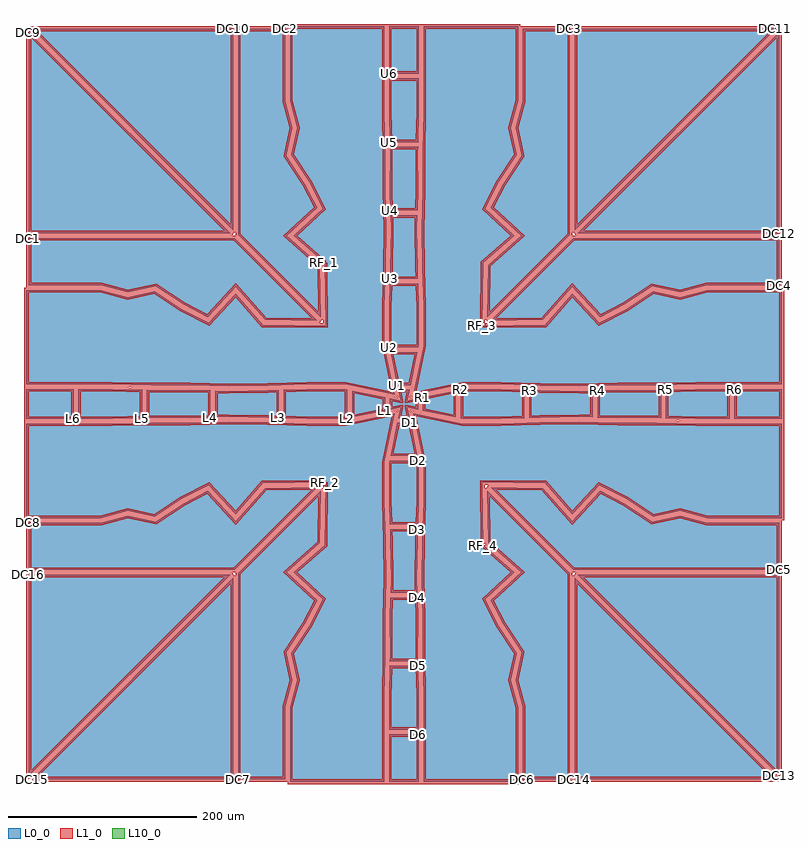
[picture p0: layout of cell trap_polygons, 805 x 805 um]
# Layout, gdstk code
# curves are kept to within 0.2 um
import gdstk
lib = gdstk.Library(unit=1e-6, precision=1e-09)
def P(c, l, *ps):  # polygons
    for p in ps: c.add(gdstk.Polygon(p, *l))
L0_0 = (0, 0)
L1_0 = (1, 0)
L10_0 = (10, 0)

trap_polygons = lib.new_cell('trap_polygons')
P(trap_polygons, L0_0, [(-397.5,-180.75),(-184.286,-180.75),(-397.5,-393.964),(-397.5,-180.75)],
  [(-393.964,-397.5),(-180.75,-184.286),(-180.75,-397.5),(-393.964,-397.5)],
  [(180.75,-397.5),(180.75,-184.286),(393.964,-397.5),(180.75,-397.5)],
  [(397.5,-393.964),(184.286,-180.75),(397.5,-180.75),(397.5,-393.964)],
  [(397.5,180.75),(184.286,180.75),(397.5,393.964),(397.5,180.75)],
  [(393.964,397.5),(180.75,184.286),(180.75,397.5),(393.964,397.5)],
  [(-180.75,397.5),(-180.75,184.286),(-393.964,397.5),(-180.75,397.5)],
  [(-397.5,393.964),(-184.286,180.75),(-397.5,180.75),(-397.5,393.964)],
  [(-397.5,-125.75),(-320.7,-125.75),(-292.572,-118.384),(-263.035,-124.717),(-232.858,-104.912),(-207.802,-92.104),(-177.951,-124.103),(-147.115,-89.006),(-91.738,-88.202),(-179.286,-175.75),(-397.5,-175.75)],
  [(-175.75,-397.5),(-175.75,-179.286),(-88.202,-91.738),(-89.006,-147.115),(-124.103,-177.951),(-92.104,-207.802),(-104.912,-232.858),(-124.717,-263.035),(-118.384,-292.572),(-125.75,-320.7),(-125.75,-397.5)],
  [(125.75,-397.5),(125.75,-320.7),(118.384,-292.572),(124.717,-263.035),(104.912,-232.858),(92.104,-207.802),(124.103,-177.951),(89.006,-147.115),(88.202,-91.738),(175.75,-179.286),(175.75,-397.5)],
  [(397.5,-175.75),(179.286,-175.75),(91.738,-88.202),(147.115,-89.006),(177.951,-124.103),(207.802,-92.104),(232.858,-104.912),(263.035,-124.717),(292.572,-118.384),(320.7,-125.75),(397.5,-125.75)],
  [(397.5,125.75),(320.7,125.75),(292.572,118.384),(263.035,124.717),(232.858,104.912),(207.802,92.104),(177.951,124.103),(147.115,89.006),(91.738,88.202),(179.286,175.75),(397.5,175.75)],
  [(175.75,397.5),(175.75,179.286),(88.202,91.738),(89.006,147.115),(124.103,177.951),(92.104,207.802),(104.912,232.858),(124.717,263.035),(118.384,292.572),(125.75,320.7),(125.75,397.5)],
  [(-125.75,397.5),(-125.75,320.7),(-118.384,292.572),(-124.717,263.035),(-104.912,232.858),(-92.104,207.802),(-124.103,177.951),(-89.006,147.115),(-88.202,91.738),(-175.75,179.286),(-175.75,397.5)],
  [(-397.5,175.75),(-179.286,175.75),(-91.738,88.202),(-147.115,89.006),(-177.951,124.103),(-207.802,92.104),(-232.858,104.912),(-263.035,124.717),(-292.572,118.384),(-320.7,125.75),(-397.5,125.75)],
  [(-15.75,350),(-15.75,400),(15.75,400),(15.75,350),(-15.75,350)],
  [(350,15.75),(400,15.75),(400,-15.75),(350,-15.75),(350,15.75)],
  [(15.75,-350),(15.75,-400),(-15.75,-400),(-15.75,-350),(15.75,-350)],
  [(-350,-15.75),(-400,-15.75),(-400,15.75),(-350,15.75),(-350,-15.75)],
  [(-15,277.5),(-15.743,309.205),(-15.75,345),(15.75,345),(15.743,309.205),(15,277.5),(-15,277.5)],
  [(277.5,15),(309.205,15.743),(345,15.75),(345,-15.75),(309.205,-15.743),(277.5,-15),(277.5,15)],
  [(15,-277.5),(15.743,-309.205),(15.75,-345),(-15.75,-345),(-15.743,-309.205),(-15,-277.5),(15,-277.5)],
  [(-277.5,-15),(-309.205,-15.743),(-345,-15.75),(-345,15.75),(-309.205,15.743),(-277.5,15),(-277.5,-15)],
  [(-14.333,205),(-14.97,226.593),(-14.772,267.734),(-14.883,272.5),(14.883,272.5),(14.772,267.734),(14.97,226.593),(14.333,205),(-14.333,205)],
  [(205,14.333),(226.593,14.97),(267.734,14.772),(272.5,14.883),(272.5,-14.883),(267.734,-14.772),(226.593,-14.97),(205,-14.333),(205,14.333)],
  [(14.333,-205),(14.97,-226.593),(14.772,-267.734),(14.883,-272.5),(-14.883,-272.5),(-14.772,-267.734),(-14.97,-226.593),(-14.333,-205),(14.333,-205)],
  [(-205,-14.333),(-226.593,-14.97),(-267.734,-14.772),(-272.5,-14.883),(-272.5,14.883),(-267.734,14.772),(-226.593,14.97),(-205,14.333),(-205,-14.333)],
  [(-14.77,132.5),(-14.386,144.098),(-13.755,185.411),(-14.185,200),(14.185,200),(13.755,185.411),(14.386,144.098),(14.77,132.5),(-14.77,132.5)],
  [(132.5,14.77),(144.098,14.386),(185.411,13.755),(200,14.185),(200,-14.185),(185.411,-13.755),(144.098,-14.386),(132.5,-14.77),(132.5,14.77)],
  [(14.77,-132.5),(14.386,-144.098),(13.755,-185.411),(14.185,-200),(-14.185,-200),(-13.755,-185.411),(-14.386,-144.098),(-14.77,-132.5),(14.77,-132.5)],
  [(-132.5,-14.77),(-144.098,-14.386),(-185.411,-13.755),(-200,-14.185),(-200,14.185),(-185.411,13.755),(-144.098,14.386),(-132.5,14.77),(-132.5,-14.77)],
  [(-15.25,60),(-15.75,62.418),(-15.75,102.98),(-14.936,127.5),(14.936,127.5),(15.75,102.98),(15.75,62.418),(15.25,60),(-15.25,60)],
  [(60,15.25),(62.418,15.75),(102.98,15.75),(127.5,14.936),(127.5,-14.936),(102.98,-15.75),(62.418,-15.75),(60,-15.25),(60,15.25)],
  [(15.25,-60),(15.75,-62.418),(15.75,-102.98),(14.936,-127.5),(-14.936,-127.5),(-15.75,-102.98),(-15.75,-62.418),(-15.25,-60),(15.25,-60)],
  [(-60,-15.25),(-62.418,-15.75),(-102.98,-15.75),(-127.5,-14.936),(-127.5,14.936),(-102.98,15.75),(-62.418,15.75),(-60,15.25),(-60,-15.25)],
  [(-6.978,20),(-14.216,55),(14.216,55),(6.978,20),(-6.978,20)],
  [(20,6.978),(55,14.216),(55,-14.216),(20,-6.978),(20,6.978)],
  [(6.978,-20),(14.216,-55),(-14.216,-55),(-6.978,-20),(6.978,-20)],
  [(-20,-6.978),(-55,-14.216),(-55,14.216),(-20,6.978),(-20,-6.978)],
  [(-5.944,15),(5.944,15),(3.584,3.584),(15,5.944),(15,-5.944),(3.584,-3.584),(5.944,-15),(-5.944,-15),(-3.584,-3.584),(-15,-5.944),(-15,5.944),(-3.584,3.584)],
  [(84.038,-149.406),(116.654,-178.062),(85.935,-206.719),(100.583,-235.375),(119.39,-264.031),(113.246,-292.687),(120.75,-321.344),(120.75,-400),(20.75,-400),(20.736,-308.844),(19.772,-267.687),(19.97,-226.531),(18.756,-185.375),(19.384,-144.219),(20.75,-103.062),(20.75,-61.906),(10.02,-10.02),(61.906,-20.75),(103.062,-20.75),(144.219,-19.384),(185.375,-18.756),(226.531,-19.97),(267.687,-19.772),(308.844,-20.736),(400,-20.75),(400,-120.75),(321.344,-120.75),(292.687,-113.246),(264.031,-119.39),(235.375,-100.583),(206.719,-85.935),(178.062,-116.654),(149.406,-84.038),(83.076,-83.076)],
  [(83.076,83.076),(149.406,84.038),(178.062,116.654),(206.719,85.935),(235.375,100.583),(264.031,119.39),(292.687,113.246),(321.344,120.75),(400,120.75),(400,20.75),(308.844,20.736),(267.687,19.772),(226.531,19.97),(185.375,18.756),(144.219,19.384),(103.062,20.75),(61.906,20.75),(10.02,10.02),(20.75,61.906),(20.75,103.062),(19.384,144.219),(18.756,185.375),(19.97,226.531),(19.772,267.687),(20.736,308.844),(20.75,400),(120.75,400),(120.75,321.344),(113.246,292.687),(119.39,264.031),(100.583,235.375),(85.935,206.719),(116.654,178.062),(84.038,149.406)],
  [(-83.076,-83.076),(-149.406,-84.038),(-178.062,-116.654),(-206.719,-85.935),(-235.375,-100.583),(-264.031,-119.39),(-292.687,-113.246),(-321.344,-120.75),(-400,-120.75),(-400,-20.75),(-308.844,-20.736),(-267.687,-19.772),(-226.531,-19.97),(-185.375,-18.756),(-144.219,-19.384),(-103.062,-20.75),(-61.906,-20.75),(-10.02,-10.02),(-20.75,-61.906),(-20.75,-103.062),(-19.384,-144.219),(-18.756,-185.375),(-19.97,-226.531),(-19.772,-267.687),(-20.736,-308.844),(-20.75,-400),(-120.75,-400),(-120.75,-321.344),(-113.246,-292.687),(-119.39,-264.031),(-100.583,-235.375),(-85.935,-206.719),(-116.654,-178.062),(-84.038,-149.406)],
  [(-84.038,149.406),(-116.654,178.062),(-85.935,206.719),(-100.583,235.375),(-119.39,264.031),(-113.246,292.687),(-120.75,321.344),(-120.75,400),(-20.75,400),(-20.736,308.844),(-19.772,267.687),(-19.97,226.531),(-18.756,185.375),(-19.384,144.219),(-20.75,103.062),(-20.75,61.906),(-10.02,10.02),(-61.906,20.75),(-103.062,20.75),(-144.219,19.384),(-185.375,18.756),(-226.531,19.97),(-267.687,19.772),(-308.844,20.736),(-400,20.75),(-400,120.75),(-321.344,120.75),(-292.687,113.246),(-264.031,119.39),(-235.375,100.583),(-206.719,85.935),(-178.062,116.654),(-149.406,84.038),(-83.076,83.076)])
P(trap_polygons, L1_0, [(-397.5,-178.25),(-397.5,-183.25),(-190.321,-183.25),(-395,-387.929),(-395,-180.75),(-400,-180.75),(-400,-396.464),(-397.5,-397.5),(-180.75,-180.75),(-181.786,-178.25)],
  [(-395.732,-395.732),(-392.197,-399.268),(-183.25,-190.321),(-183.25,-395),(-393.964,-395),(-393.964,-400),(-178.25,-400),(-178.25,-181.786),(-180.75,-180.75)],
  [(178.25,-397.5),(183.25,-397.5),(183.25,-190.321),(387.929,-395),(180.75,-395),(180.75,-400),(396.464,-400),(397.5,-397.5),(180.75,-180.75),(178.25,-181.786)],
  [(395.732,-395.732),(399.268,-392.197),(190.321,-183.25),(395,-183.25),(395,-393.964),(400,-393.964),(400,-178.25),(181.786,-178.25),(180.75,-180.75)],
  [(397.5,178.25),(397.5,183.25),(190.321,183.25),(395,387.929),(395,180.75),(400,180.75),(400,396.464),(397.5,397.5),(180.75,180.75),(181.786,178.25)],
  [(395.732,395.732),(392.197,399.268),(183.25,190.321),(183.25,395),(393.964,395),(393.964,400),(178.25,400),(178.25,181.786),(180.75,180.75)],
  [(-178.25,397.5),(-183.25,397.5),(-183.25,190.321),(-387.929,395),(-180.75,395),(-180.75,400),(-396.464,400),(-397.5,397.5),(-180.75,180.75),(-178.25,181.786)],
  [(-395.732,395.732),(-399.268,392.197),(-190.321,183.25),(-395,183.25),(-395,393.964),(-400,393.964),(-400,178.25),(-181.786,178.25),(-180.75,180.75)],
  [(-397.5,-123.25),(-397.5,-128.25),(-320.378,-128.25),(-292.514,-120.954),(-262.538,-127.38),(-231.6,-107.077),(-208.343,-95.189),(-178.074,-127.637),(-177.723,-127.632),(-145.969,-91.489),(-97.862,-90.791),(-180.321,-173.25),(-395,-173.25),(-395,-125.75),(-400,-125.75),(-400,-178.25),(-178.25,-178.25),(-88.202,-88.202),(-89.274,-85.666),(-148.261,-86.522),(-178.007,-120.379),(-207.26,-89.02),(-234.117,-102.748),(-263.533,-122.053),(-292.63,-115.815),(-321.022,-123.25)],
  [(-178.25,-397.5),(-173.25,-397.5),(-173.25,-180.321),(-90.791,-97.862),(-91.489,-145.969),(-127.632,-177.723),(-127.637,-178.074),(-95.189,-208.343),(-107.077,-231.6),(-127.38,-262.538),(-120.954,-292.514),(-128.25,-320.378),(-128.25,-395),(-175.75,-395),(-175.75,-400),(-123.25,-400),(-123.25,-321.022),(-115.815,-292.63),(-122.053,-263.533),(-102.748,-234.117),(-89.02,-207.26),(-120.379,-178.007),(-86.522,-148.261),(-85.666,-89.274),(-88.202,-88.202),(-178.25,-178.25)],
  [(123.25,-397.5),(128.25,-397.5),(128.25,-320.378),(120.954,-292.514),(127.38,-262.538),(107.077,-231.6),(95.189,-208.343),(127.637,-178.074),(127.632,-177.723),(91.489,-145.969),(90.791,-97.862),(173.25,-180.321),(173.25,-395),(125.75,-395),(125.75,-400),(178.25,-400),(178.25,-178.25),(88.202,-88.202),(85.666,-89.274),(86.522,-148.261),(120.379,-178.007),(89.02,-207.26),(102.748,-234.117),(122.053,-263.533),(115.815,-292.63),(123.25,-321.022)],
  [(397.5,-178.25),(397.5,-173.25),(180.321,-173.25),(97.862,-90.791),(145.969,-91.489),(177.723,-127.632),(178.074,-127.637),(208.343,-95.189),(231.6,-107.077),(262.538,-127.38),(292.514,-120.954),(320.378,-128.25),(395,-128.25),(395,-175.75),(400,-175.75),(400,-123.25),(321.022,-123.25),(292.63,-115.815),(263.533,-122.053),(234.117,-102.748),(207.26,-89.02),(178.007,-120.379),(148.261,-86.522),(89.274,-85.666),(88.202,-88.202),(178.25,-178.25)],
  [(397.5,123.25),(397.5,128.25),(320.378,128.25),(292.514,120.954),(262.538,127.38),(231.6,107.077),(208.343,95.189),(178.074,127.637),(177.723,127.632),(145.969,91.489),(97.862,90.791),(180.321,173.25),(395,173.25),(395,125.75),(400,125.75),(400,178.25),(178.25,178.25),(88.202,88.202),(89.274,85.666),(148.261,86.522),(178.007,120.379),(207.26,89.02),(234.117,102.748),(263.533,122.053),(292.63,115.815),(321.022,123.25)],
  [(178.25,397.5),(173.25,397.5),(173.25,180.321),(90.791,97.862),(91.489,145.969),(127.632,177.723),(127.637,178.074),(95.189,208.343),(107.077,231.6),(127.38,262.538),(120.954,292.514),(128.25,320.378),(128.25,395),(175.75,395),(175.75,400),(123.25,400),(123.25,321.022),(115.815,292.63),(122.053,263.533),(102.748,234.117),(89.02,207.26),(120.379,178.007),(86.522,148.261),(85.666,89.274),(88.202,88.202),(178.25,178.25)],
  [(-123.25,397.5),(-128.25,397.5),(-128.25,320.378),(-120.954,292.514),(-127.38,262.538),(-107.077,231.6),(-95.189,208.343),(-127.637,178.074),(-127.632,177.723),(-91.489,145.969),(-90.791,97.862),(-173.25,180.321),(-173.25,395),(-125.75,395),(-125.75,400),(-178.25,400),(-178.25,178.25),(-88.202,88.202),(-85.666,89.274),(-86.522,148.261),(-120.379,178.007),(-89.02,207.26),(-102.748,234.117),(-122.053,263.533),(-115.815,292.63),(-123.25,321.022)],
  [(-397.5,178.25),(-397.5,173.25),(-180.321,173.25),(-97.862,90.791),(-145.969,91.489),(-177.723,127.632),(-178.074,127.637),(-208.343,95.189),(-231.6,107.077),(-262.538,127.38),(-292.514,120.954),(-320.378,128.25),(-395,128.25),(-395,175.75),(-400,175.75),(-400,123.25),(-321.022,123.25),(-292.63,115.815),(-263.533,122.053),(-234.117,102.748),(-207.26,89.02),(-178.007,120.379),(-148.261,86.522),(-89.274,85.666),(-88.202,88.202),(-178.25,178.25)],
  [(-18.25,350),(-13.25,350),(-13.25,397.5),(13.25,397.5),(13.25,352.5),(-15.75,352.5),(-15.75,347.5),(18.25,347.5),(18.25,402.5),(-18.25,402.5)],
  [(350,18.25),(350,13.25),(397.5,13.25),(397.5,-13.25),(352.5,-13.25),(352.5,15.75),(347.5,15.75),(347.5,-18.25),(402.5,-18.25),(402.5,18.25)],
  [(18.25,-350),(13.25,-350),(13.25,-397.5),(-13.25,-397.5),(-13.25,-352.5),(15.75,-352.5),(15.75,-347.5),(-18.25,-347.5),(-18.25,-402.5),(18.25,-402.5)],
  [(-350,-18.25),(-350,-13.25),(-397.5,-13.25),(-397.5,13.25),(-352.5,13.25),(-352.5,-15.75),(-347.5,-15.75),(-347.5,18.25),(-402.5,18.25),(-402.5,-18.25)],
  [(-17.5,277.441),(-12.501,277.559),(-13.243,309.235),(-13.249,342.5),(13.249,342.5),(13.243,309.235),(12.558,280),(-15,280),(-15,275),(17.443,275),(18.243,309.176),(18.25,347.5),(-18.251,347.499),(-18.243,309.176)],
  [(277.441,17.5),(277.559,12.501),(309.235,13.243),(342.5,13.249),(342.5,-13.249),(309.235,-13.243),(280,-12.558),(280,15),(275,15),(275,-17.443),(309.176,-18.243),(347.5,-18.25),(347.499,18.251),(309.176,18.243)],
  [(17.5,-277.441),(12.501,-277.559),(13.243,-309.235),(13.249,-342.5),(-13.249,-342.5),(-13.243,-309.235),(-12.558,-280),(15,-280),(15,-275),(-17.443,-275),(-18.243,-309.176),(-18.25,-347.5),(18.251,-347.499),(18.243,-309.176)],
  [(-277.441,-17.5),(-277.559,-12.501),(-309.235,-13.243),(-342.5,-13.249),(-342.5,13.249),(-309.235,13.243),(-280,12.558),(-280,-15),(-275,-15),(-275,17.443),(-309.176,18.243),(-347.5,18.25),(-347.499,-18.251),(-309.176,-18.243)],
  [(-16.832,204.926),(-11.834,205.074),(-12.47,226.624),(-12.324,270),(12.324,270),(12.47,226.624),(11.906,207.5),(-14.333,207.5),(-14.333,202.5),(16.76,202.5),(17.47,226.562),(17.383,275),(-17.441,274.941),(-17.47,226.562)],
  [(204.926,16.832),(205.074,11.834),(226.624,12.47),(270,12.324),(270,-12.324),(226.624,-12.47),(207.5,-11.906),(207.5,14.333),(202.5,14.333),(202.5,-16.76),(226.562,-17.47),(275,-17.383),(274.941,17.441),(226.562,17.47)],
  [(16.832,-204.926),(11.834,-205.074),(12.47,-226.624),(12.324,-270),(-12.324,-270),(-12.47,-226.624),(-11.906,-207.5),(14.333,-207.5),(14.333,-202.5),(-16.76,-202.5),(-17.47,-226.562),(-17.383,-275),(17.441,-274.941),(17.47,-226.562)],
  [(-204.926,-16.832),(-205.074,-11.834),(-226.624,-12.47),(-270,-12.324),(-270,12.324),(-226.624,12.47),(-207.5,11.906),(-207.5,-14.333),(-202.5,-14.333),(-202.5,16.76),(-226.562,17.47),(-275,17.383),(-274.941,-17.441),(-226.562,-17.47)],
  [(-17.269,132.583),(-12.272,132.417),(-11.254,185.428),(-11.611,197.5),(11.611,197.5),(11.254,185.428),(12.186,135),(-14.77,135),(-14.77,130),(17.352,130.084),(16.256,185.393),(16.685,202.5),(-16.758,202.425),(-16.256,185.393)],
  [(132.583,17.269),(132.417,12.272),(185.428,11.254),(197.5,11.611),(197.5,-11.611),(185.428,-11.254),(135,-12.186),(135,14.77),(130,14.77),(130.084,-17.352),(185.393,-16.256),(202.5,-16.685),(202.425,16.758),(185.393,16.256)],
  [(17.269,-132.583),(12.272,-132.417),(11.254,-185.428),(11.611,-197.5),(-11.611,-197.5),(-11.254,-185.428),(-12.186,-135),(14.77,-135),(14.77,-130),(-17.352,-130.084),(-16.256,-185.393),(-16.685,-202.5),(16.758,-202.425),(16.256,-185.393)],
  [(-132.583,-17.269),(-132.417,-12.272),(-185.428,-11.254),(-197.5,-11.611),(-197.5,11.611),(-185.428,11.254),(-135,12.186),(-135,-14.77),(-130,-14.77),(-130.084,17.352),(-185.393,16.256),(-202.5,16.685),(-202.425,-16.758),(-185.393,-16.256)],
  [(-17.698,59.494),(-12.802,60.506),(-13.25,62.674),(-13.25,102.938),(-12.518,125),(12.518,125),(13.25,102.938),(13.214,62.5),(-15.25,62.5),(-15.25,57.5),(17.286,57.5),(18.25,62.162),(18.25,103.021),(17.355,130),(-17.355,130),(-18.25,103.021),(-18.25,62.162)],
  [(59.494,17.698),(60.506,12.802),(62.674,13.25),(102.938,13.25),(125,12.518),(125,-12.518),(102.938,-13.25),(62.5,-13.214),(62.5,15.25),(57.5,15.25),(57.5,-17.286),(62.162,-18.25),(103.021,-18.25),(130,-17.355),(130,17.355),(103.021,18.25),(62.162,18.25)],
  [(17.698,-59.494),(12.802,-60.506),(13.25,-62.674),(13.25,-102.938),(12.518,-125),(-12.518,-125),(-13.25,-102.938),(-13.214,-62.5),(15.25,-62.5),(15.25,-57.5),(-17.286,-57.5),(-18.25,-62.162),(-18.25,-103.021),(-17.355,-130),(17.355,-130),(18.25,-103.021),(18.25,-62.162)],
  [(-59.494,-17.698),(-60.506,-12.802),(-62.674,-13.25),(-102.938,-13.25),(-125,-12.518),(-125,12.518),(-102.938,13.25),(-62.5,13.214),(-62.5,-15.25),(-57.5,-15.25),(-57.5,17.286),(-62.162,18.25),(-103.021,18.25),(-130,17.355),(-130,-17.355),(-103.021,-18.25),(-62.162,-18.25)],
  [(-9.427,19.494),(-4.53,20.506),(-11.146,52.5),(11.146,52.5),(4.942,22.5),(-6.978,22.5),(-6.978,17.5),(9.014,17.5),(17.171,56.942),(16.716,57.5),(-16.716,57.5),(-17.171,56.942)],
  [(19.494,9.427),(20.506,4.53),(52.5,11.146),(52.5,-11.146),(22.5,-4.942),(22.5,6.978),(17.5,6.978),(17.5,-9.014),(56.942,-17.171),(57.5,-16.716),(57.5,16.716),(56.942,17.171)],
  [(9.427,-19.494),(4.53,-20.506),(11.146,-52.5),(-11.146,-52.5),(-4.942,-22.5),(6.978,-22.5),(6.978,-17.5),(-9.014,-17.5),(-17.171,-56.942),(-16.716,-57.5),(16.716,-57.5),(17.171,-56.942)],
  [(-19.494,-9.427),(-20.506,-4.53),(-52.5,-11.146),(-52.5,11.146),(-22.5,4.942),(-22.5,-6.978),(-17.5,-6.978),(-17.5,9.014),(-56.942,17.171),(-57.5,16.716),(-57.5,-16.716),(-56.942,-17.171)],
  [(-5.944,17.5),(-5.944,12.5),(2.875,12.5),(0.629,1.642),(1.642,0.629),(12.5,2.875),(12.5,-2.875),(1.642,-0.629),(0.629,-1.642),(2.875,-12.5),(-2.875,-12.5),(-0.629,-1.642),(-1.642,-0.629),(-12.5,-2.875),(-12.5,2.875),(-1.642,0.629),(-0.629,1.642),(-3.496,15.506),(-8.393,14.494),(-6.802,6.802),(-16.942,8.899),(-17.5,8.444),(-17.5,-8.444),(-16.942,-8.899),(-6.802,-6.802),(-8.899,-16.942),(-8.444,-17.5),(8.444,-17.5),(8.899,-16.942),(6.802,-6.802),(16.942,-8.899),(17.5,-8.444),(17.5,8.444),(16.942,8.899),(6.802,6.802),(8.899,16.942),(8.444,17.5)],
  [(85.688,-147.528),(82.388,-151.284),(112.93,-178.118),(82.851,-206.177),(98.419,-236.633),(116.726,-264.529),(110.677,-292.745),(118.25,-321.666),(118.25,-397.5),(23.25,-397.5),(23.235,-308.814),(22.272,-267.664),(22.47,-226.5),(21.257,-185.357),(21.884,-144.279),(23.25,-103.104),(23.25,-61.65),(13.239,-13.239),(61.65,-23.25),(103.104,-23.25),(144.279,-21.884),(185.357,-21.257),(226.5,-22.47),(267.664,-22.272),(308.814,-23.235),(397.5,-23.25),(397.5,-118.25),(321.666,-118.25),(292.745,-110.677),(264.529,-116.726),(236.633,-98.419),(206.177,-82.851),(178.118,-112.93),(150.552,-81.555),(80.613,-80.54),(81.538,-149.443),(86.538,-149.37),(85.613,-85.613),(148.261,-86.522),(177.834,-120.183),(178.185,-120.188),(207.26,-89.02),(234.117,-102.748),(263.533,-122.053),(292.63,-115.815),(321.022,-123.25),(402.5,-123.25),(402.5,-18.25),(308.873,-18.236),(267.711,-17.272),(226.562,-17.47),(185.393,-16.256),(144.158,-16.885),(103.021,-18.25),(62.162,-18.25),(8.079,-7.066),(7.066,-8.079),(18.25,-62.162),(18.25,-103.021),(16.885,-144.158),(16.256,-185.393),(17.47,-226.562),(17.272,-267.711),(18.236,-308.873),(18.25,-402.5),(123.25,-402.5),(123.25,-321.022),(115.815,-292.63),(122.053,-263.533),(102.748,-234.117),(89.02,-207.26),(120.188,-178.185),(120.183,-177.834)],
  [(83.04,85.576),(83.112,80.576),(150.552,81.555),(178.118,112.93),(206.177,82.851),(236.633,98.419),(264.529,116.726),(292.745,110.677),(321.666,118.25),(397.5,118.25),(397.5,23.25),(308.814,23.235),(267.664,22.272),(226.5,22.47),(185.357,21.257),(144.279,21.884),(103.104,23.25),(61.65,23.25),(13.239,13.239),(23.25,61.65),(23.25,103.104),(21.884,144.279),(21.257,185.357),(22.47,226.5),(22.272,267.664),(23.235,308.814),(23.25,397.5),(118.25,397.5),(118.25,321.666),(110.677,292.745),(116.726,264.529),(98.419,236.633),(82.851,206.177),(112.93,178.118),(81.555,150.552),(80.576,83.112),(85.576,83.04),(86.522,148.261),(120.183,177.834),(120.188,178.185),(89.02,207.26),(102.748,234.117),(122.053,263.533),(115.815,292.63),(123.25,321.022),(123.25,402.5),(18.25,402.5),(18.236,308.873),(17.272,267.711),(17.47,226.562),(16.256,185.393),(16.885,144.158),(18.25,103.021),(18.25,62.162),(7.066,8.079),(8.079,7.066),(62.162,18.25),(103.021,18.25),(144.158,16.885),(185.393,16.256),(226.562,17.47),(267.711,17.272),(308.873,18.236),(402.5,18.25),(402.5,123.25),(321.022,123.25),(292.63,115.815),(263.533,122.053),(234.117,102.748),(207.26,89.02),(178.185,120.188),(177.834,120.183),(148.261,86.522)],
  [(-83.04,-85.576),(-83.112,-80.576),(-150.552,-81.555),(-178.118,-112.93),(-206.177,-82.851),(-236.633,-98.419),(-264.529,-116.726),(-292.745,-110.677),(-321.666,-118.25),(-397.5,-118.25),(-397.5,-23.25),(-308.814,-23.235),(-267.664,-22.272),(-226.5,-22.47),(-185.357,-21.257),(-144.279,-21.884),(-103.104,-23.25),(-61.65,-23.25),(-13.239,-13.239),(-23.25,-61.65),(-23.25,-103.104),(-21.884,-144.279),(-21.257,-185.357),(-22.47,-226.5),(-22.272,-267.664),(-23.235,-308.814),(-23.25,-397.5),(-118.25,-397.5),(-118.25,-321.666),(-110.677,-292.745),(-116.726,-264.529),(-98.419,-236.633),(-82.851,-206.177),(-112.93,-178.118),(-81.555,-150.552),(-80.576,-83.112),(-85.576,-83.04),(-86.522,-148.261),(-120.183,-177.834),(-120.188,-178.185),(-89.02,-207.26),(-102.748,-234.117),(-122.053,-263.533),(-115.815,-292.63),(-123.25,-321.022),(-123.25,-402.5),(-18.25,-402.5),(-18.236,-308.873),(-17.272,-267.711),(-17.47,-226.562),(-16.256,-185.393),(-16.885,-144.158),(-18.25,-103.021),(-18.25,-62.162),(-7.066,-8.079),(-8.079,-7.066),(-62.162,-18.25),(-103.021,-18.25),(-144.158,-16.885),(-185.393,-16.256),(-226.562,-17.47),(-267.711,-17.272),(-308.873,-18.236),(-402.5,-18.25),(-402.5,-123.25),(-321.022,-123.25),(-292.63,-115.815),(-263.533,-122.053),(-234.117,-102.748),(-207.26,-89.02),(-178.185,-120.188),(-177.834,-120.183),(-148.261,-86.522)],
  [(-85.688,147.528),(-82.388,151.284),(-112.93,178.118),(-82.851,206.177),(-98.419,236.633),(-116.726,264.529),(-110.677,292.745),(-118.25,321.666),(-118.25,397.5),(-23.25,397.5),(-23.235,308.814),(-22.272,267.664),(-22.47,226.5),(-21.257,185.357),(-21.884,144.279),(-23.25,103.104),(-23.25,61.65),(-13.239,13.239),(-61.65,23.25),(-103.104,23.25),(-144.279,21.884),(-185.357,21.257),(-226.5,22.47),(-267.664,22.272),(-308.814,23.235),(-397.5,23.25),(-397.5,118.25),(-321.666,118.25),(-292.745,110.677),(-264.529,116.726),(-236.633,98.419),(-206.177,82.851),(-178.118,112.93),(-150.552,81.555),(-80.613,80.54),(-81.538,149.443),(-86.538,149.37),(-85.613,85.613),(-148.261,86.522),(-177.834,120.183),(-178.185,120.188),(-207.26,89.02),(-234.117,102.748),(-263.533,122.053),(-292.63,115.815),(-321.022,123.25),(-402.5,123.25),(-402.5,18.25),(-308.873,18.236),(-267.711,17.272),(-226.562,17.47),(-185.393,16.256),(-144.158,16.885),(-103.021,18.25),(-62.162,18.25),(-8.079,7.066),(-7.066,8.079),(-18.25,62.162),(-18.25,103.021),(-16.885,144.158),(-16.256,185.393),(-17.47,226.562),(-17.272,267.711),(-18.236,308.873),(-18.25,402.5),(-123.25,402.5),(-123.25,321.022),(-115.815,292.63),(-122.053,263.533),(-102.748,234.117),(-89.02,207.26),(-120.188,178.185),(-120.183,177.834)])
P(trap_polygons, L10_0, [(0,0),(0,0),(0,0),(0,0)])
trap_polygons.add(gdstk.Label('DC16', (-397.5,-180.75), layer=2, texttype=0))
trap_polygons.add(gdstk.Label('DC15', (-393.964,-397.5), layer=2, texttype=0))
trap_polygons.add(gdstk.Label('DC14', (180.75,-397.5), layer=2, texttype=0))
trap_polygons.add(gdstk.Label('DC13', (397.5,-393.964), layer=2, texttype=0))
trap_polygons.add(gdstk.Label('DC12', (397.5,180.75), layer=2, texttype=0))
trap_polygons.add(gdstk.Label('DC11', (393.964,397.5), layer=2, texttype=0))
trap_polygons.add(gdstk.Label('DC10', (-180.75,397.5), layer=2, texttype=0))
trap_polygons.add(gdstk.Label('DC9', (-397.5,393.964), layer=2, texttype=0))
trap_polygons.add(gdstk.Label('DC8', (-397.5,-125.75), layer=2, texttype=0))
trap_polygons.add(gdstk.Label('DC7', (-175.75,-397.5), layer=2, texttype=0))
trap_polygons.add(gdstk.Label('DC6', (125.75,-397.5), layer=2, texttype=0))
trap_polygons.add(gdstk.Label('DC5', (397.5,-175.75), layer=2, texttype=0))
trap_polygons.add(gdstk.Label('DC4', (397.5,125.75), layer=2, texttype=0))
trap_polygons.add(gdstk.Label('DC3', (175.75,397.5), layer=2, texttype=0))
trap_polygons.add(gdstk.Label('DC2', (-125.75,397.5), layer=2, texttype=0))
trap_polygons.add(gdstk.Label('DC1', (-397.5,175.75), layer=2, texttype=0))
trap_polygons.add(gdstk.Label('U6', (-15.75,350), layer=2, texttype=0))
trap_polygons.add(gdstk.Label('R6', (350,15.75), layer=2, texttype=0))
trap_polygons.add(gdstk.Label('D6', (15.75,-350), layer=2, texttype=0))
trap_polygons.add(gdstk.Label('L6', (-350,-15.75), layer=2, texttype=0))
trap_polygons.add(gdstk.Label('U5', (-15,277.5), layer=2, texttype=0))
trap_polygons.add(gdstk.Label('R5', (277.5,15), layer=2, texttype=0))
trap_polygons.add(gdstk.Label('D5', (15,-277.5), layer=2, texttype=0))
trap_polygons.add(gdstk.Label('L5', (-277.5,-15), layer=2, texttype=0))
trap_polygons.add(gdstk.Label('U4', (-14.333,205), layer=2, texttype=0))
trap_polygons.add(gdstk.Label('R4', (205,14.333), layer=2, texttype=0))
trap_polygons.add(gdstk.Label('D4', (14.333,-205), layer=2, texttype=0))
trap_polygons.add(gdstk.Label('L4', (-205,-14.333), layer=2, texttype=0))
trap_polygons.add(gdstk.Label('U3', (-14.77,132.5), layer=2, texttype=0))
trap_polygons.add(gdstk.Label('R3', (132.5,14.77), layer=2, texttype=0))
trap_polygons.add(gdstk.Label('D3', (14.77,-132.5), layer=2, texttype=0))
trap_polygons.add(gdstk.Label('L3', (-132.5,-14.77), layer=2, texttype=0))
trap_polygons.add(gdstk.Label('U2', (-15.25,60), layer=2, texttype=0))
trap_polygons.add(gdstk.Label('R2', (60,15.25), layer=2, texttype=0))
trap_polygons.add(gdstk.Label('D2', (15.25,-60), layer=2, texttype=0))
trap_polygons.add(gdstk.Label('L2', (-60,-15.25), layer=2, texttype=0))
trap_polygons.add(gdstk.Label('U1', (-6.978,20), layer=2, texttype=0))
trap_polygons.add(gdstk.Label('R1', (20,6.978), layer=2, texttype=0))
trap_polygons.add(gdstk.Label('D1', (6.978,-20), layer=2, texttype=0))
trap_polygons.add(gdstk.Label('L1', (-20,-6.978), layer=2, texttype=0))
trap_polygons.add(gdstk.Label('C', (-5.944,15), layer=2, texttype=0))
trap_polygons.add(gdstk.Label('RF_4', (84.038,-149.406), layer=2, texttype=0))
trap_polygons.add(gdstk.Label('RF_3', (83.076,83.076), layer=2, texttype=0))
trap_polygons.add(gdstk.Label('RF_2', (-83.076,-83.076), layer=2, texttype=0))
trap_polygons.add(gdstk.Label('RF_1', (-84.038,149.406), layer=2, texttype=0))

lib.write_gds('trap_polygons.gds')
